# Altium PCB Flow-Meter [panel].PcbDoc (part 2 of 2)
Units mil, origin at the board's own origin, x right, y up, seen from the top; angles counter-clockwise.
Board outline 669.29 x 748.03 mil, 2 copper layers (Top Layer, Bottom Layer), stack 61.855 mil thick; 0 components, 7 nets, 832 pads, 0 vias.

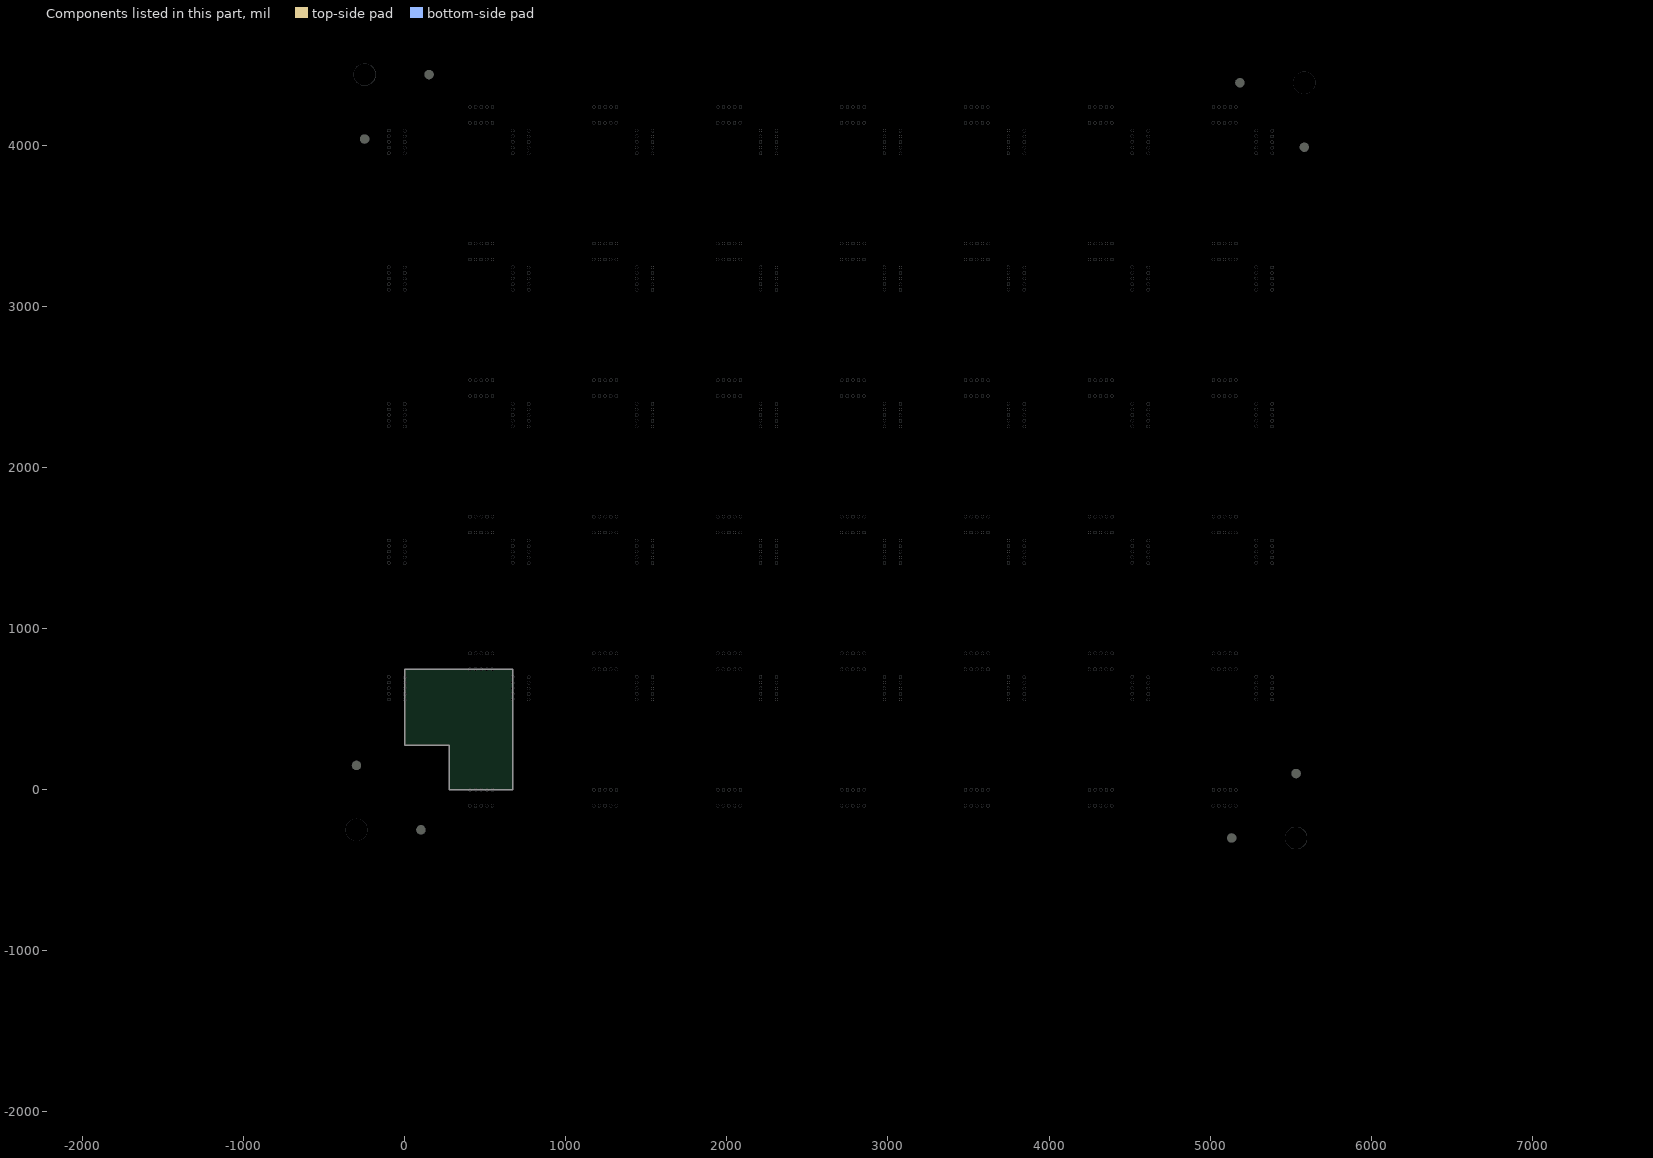
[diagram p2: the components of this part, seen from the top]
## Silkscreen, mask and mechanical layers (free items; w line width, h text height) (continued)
Bottom Paste:
  lines w7.87: -2070.08,-1784.25 1512.6,-1784.25 2142.52,-1784.25 2772.44,-1784.25 3402.36,-1784.25 4032.28,-1784.25 ; -2070.08,-1587.4 1512.6,-1587.4 5292.13,-1587.4 ; -1203.94,-1981.1 -1203.94,-1587.4 ; -692.13,-1981.1 -692.13,-1587.4 ; 803.94,-1981.1 803.94,-1587.4 ; 2142.52,-1981.1 2142.52,-1587.4 ; 2772.44,-1981.1 2772.44,-1587.4 ; 3402.36,-1981.1 3402.36,-1587.4 ; 4032.28,-1587.4 4032.28,-1981.1 4032.28,-1784.25 ; 4662.2,-1981.1 4662.2,-1587.4 ; 5626.77,-1981.1 5626.77,-1784.25 ; 7044.09,-1981.1 7044.09,-1784.25 ; 7536.22,-1784.25 5292.13,-1784.25 ; 1512.6,-1981.1 7536.22,-1981.1 7536.22,-800 5922.05,-800 5292.13,-800 ; 1512.6,-1981.1 1512.6,-800 ; 1512.6,-1981.1 -2070.08,-1981.1 -2070.08,-800 1512.6,-800 ; 1512.6,-800 5292.13,-800 ; 4032.28,-1784.25 4662.2,-1784.25 5292.13,-1784.25 ; 5292.13,-1784.25 5292.13,-1981.1 5292.13,-1784.25 ; 5292.13,-1784.25 5292.13,-800
  text "TITLE" at 1433.86,-918.11 h98.43
  text "NOTES:" at 5233.07,-918.11 h98.43
  text "1) PADS ARE 1:1 REDUCTION TO BE SPECIFIED BY THE ASSEMBLER" at 5233.07,-1036.22 h98.43
  text "2) VIEW ON SQUEEGEE SIDE DO NOT MIRROR" at 5233.07,-1154.33 h98.43
  text "AGRIGEL" at 7362.02,-1171.02 h393.7
  text ".PCB_TITLE" at 1315.75,-1233.07 h196.85
  text "3) STENCIL TYPE AND FRAMING TO BE SPECIFIED BY THE ASSEMBLER" at 5233.07,-1272.44 h98.43
  text "BOTTOM SIDE SOLDER STENCIL" at 1276.38,-1351.18 h98.43
  text "4) INDICATED FRAME REPRESENTS MAXIMIUM PANEL SIZE AND MUST" at 5233.07,-1390.55 h98.43
  text "BE CENTERED ON THE SOLDER STENCIL" at 5114.96,-1508.66 h98.43
  text "SHEET NO." at -1282.68,-1705.51 h98.43
  text "PCB VER" at -731.5,-1705.51 h98.43
  text ".PCB_Drawing Number" at 725.2,-1705.51 h98.43
  text "DWG NUMBER" at 1473.23,-1705.51 h98.43
  text ".PCB_ECRNo" at 1985.04,-1705.51 h98.43
  text ".PCB_DocRevision" at 2733.07,-1705.51 h98.43
  text ".PRINT_DATE" at 3284.25,-1705.51 h98.43
  text ".PCB_Approved" at 3914.17,-1705.51 h98.43
  text ".PCB_Checked" at 4544.09,-1705.51 h98.43
  text ".PCB_Drawn" at 5134.64,-1705.51 h98.43
  text "2" at -1951.97,-1902.36 h98.43
  text "OF" at -1755.12,-1902.36 h98.43
  text "2" at -1637.01,-1902.36 h98.43
  text "SHEET" at -1282.68,-1902.36 h98.43
  text ".Version" at -810.24,-1902.36 h98.43
  text ".Pcb_File_Name_No_Path" at 725.2,-1902.36 h98.43
  text "SOURCE" at 1473.23,-1902.36 h98.43
  text "ECR NO." at 1985.04,-1902.36 h98.43
  text "DOC REV." at 2654.33,-1902.36 h98.43
  text "DATE" at 3205.51,-1902.36 h98.43
  text "APPROVED" at 3953.54,-1902.36 h98.43
  text "CHECKED" at 4544.09,-1902.36 h98.43
  text "DRAWN" at 5134.64,-1902.36 h98.43
  text "GBP" at 5587.4,-1902.36 h98.43
  text ".PCB_Plot File" at 7004.72,-1902.36 h98.43
  text "PLOTFILE" at 7496.85,-1902.36 h98.43
Top Solder:
  circle w7.87: c-1000,-300 r98.43
  circle w7.87: c-1000,-300 r19.69
  circle w7.87: c-1000,-300 r59.06
  circle w7.87: c-1000,4440 r98.43
  circle w7.87: c-1000,4440 r19.69
  circle w7.87: c-1000,4440 r59.06
  circle w7.87: c6300,-300 r98.43
  circle w7.87: c6300,-300 r19.69
  circle w7.87: c6300,-300 r59.06
  rectangle: 1091.73,4336.02 1308.46,4463.98
  rectangle: 3891.73,-363.98 4108.46,-236.02
  lines w7.87: -2063.78,-1784.25 180.31,-1784.25 ; -1571.65,-1981.1 -1571.65,-1784.25 ; -1118.11,-300 -1000,-300 ; -1118.11,4440 -1000,4440 ; -1000,-418.11 -1000,-300 ; -1000,-181.89 -1000,-300 ; -1000,4321.89 -1000,4440 ; -1000,4558.11 -1000,4440 ; -881.89,-300 -1000,-300 ; -881.89,4440 -1000,4440 ; -154.33,-1981.1 -154.33,-1784.25 ; 180.31,-1981.1 180.31,-1784.25 ; 180.31,-1587.4 3959.84,-1587.4 7542.52,-1587.4 ; 180.31,-1390.55 3959.84,-1390.55 ; 180.31,-1193.7 3959.84,-1193.7 ; 180.31,-996.85 3959.84,-996.85 ; 810.24,-1981.1 810.24,-800 ; 1440.16,-800 1440.16,-1981.1 1440.16,-1784.25 ; 2070.08,-1981.1 2070.08,-800 ; 2700,-1981.1 2700,-800 ; 3329.92,-1981.1 3329.92,-800 ; 4668.5,-1981.1 4668.5,-1587.4 ; 6164.57,-1981.1 6164.57,-1587.4 ; 6181.89,-300 6300,-300 ; 6300,-418.11 6300,-300 ; 6300,-181.89 6300,-300 ; 6418.11,-300 6300,-300 ; 6676.38,-1981.1 6676.38,-1587.4 ; 7542.52,-1784.25 3959.84,-1784.25 3329.92,-1784.25 2700,-1784.25 2070.08,-1784.25 1440.16,-1784.25 ; 180.31,-1784.25 810.24,-1784.25 1440.16,-1784.25 ; 180.31,-1784.25 180.31,-800 ; 180.31,-800 3959.84,-800 ; 180.31,-800 -449.61,-800 -2063.78,-800 -2063.78,-1981.1 3959.84,-1981.1 ; 3959.84,-1981.1 7542.52,-1981.1 7542.52,-800 3959.84,-800 ; 3959.84,-1981.1 3959.84,-800
  text "TITLE" at 4038.58,-918.11 h98.43
  text "AGRIGEL" at -1896.32,-1171.02 h393.7
  text ".PCB_TITLE" at 4156.69,-1233.07 h196.85
  text "TOP SIDE SOLDER MASK" at 4156.69,-1390.55 h98.43
  text ".PCB_Drawn" at 337.8,-1705.51 h98.43
  text ".PCB_Checked" at 928.35,-1705.51 h98.43
  text ".PCB_Approved" at 1558.27,-1705.51 h98.43
  text ".PRINT_DATE" at 2188.19,-1705.51 h98.43
  text ".PCB_DocRevision" at 2739.37,-1705.51 h98.43
  text ".PCB_ECRNo" at 3487.4,-1705.51 h98.43
  text "DWG NUMBER" at 3999.21,-1705.51 h98.43
  text ".PCB_Drawing Number" at 4747.24,-1705.51 h98.43
  text "PCB VER" at 6203.94,-1705.51 h98.43
  text "SHEET NO." at 6755.12,-1705.51 h98.43
  text "PLOTFILE" at -2024.41,-1902.36 h98.43
  text ".PCB_Plot File" at -1532.28,-1902.36 h98.43
  text "GTS" at -114.96,-1902.36 h98.43
  text "DRAWN" at 337.8,-1902.36 h98.43
  text "CHECKED" at 928.35,-1902.36 h98.43
  text "APPROVED" at 1518.9,-1902.36 h98.43
  text "DATE" at 2266.93,-1902.36 h98.43
  text "DOC REV." at 2818.11,-1902.36 h98.43
  text "ECR NO." at 3487.4,-1902.36 h98.43
  text "SOURCE" at 3999.21,-1902.36 h98.43
  text ".Pcb_File_Name_No_Path" at 4747.24,-1902.36 h98.43
  text ".Version" at 6282.68,-1902.36 h98.43
  text "SHEET" at 6755.12,-1902.36 h98.43
  text "3" at 7109.45,-1902.36 h98.43
  text "OF" at 7227.56,-1902.36 h98.43
  text "7" at 7424.41,-1902.36 h98.43
Bottom Solder:
  circle w7.87: c-1000,-300 r98.43
  circle w7.87: c-1000,-300 r19.69
  circle w7.87: c-1000,-300 r59.06
  circle w7.87: c-1000,4440 r98.43
  circle w7.87: c-1000,4440 r19.69
  circle w7.87: c-1000,4440 r59.06
  circle w7.87: c6300,-300 r98.43
  circle w7.87: c6300,-300 r19.69
  circle w7.87: c6300,-300 r59.06
  rectangle: 1091.73,4336.02 1308.46,4463.98
  rectangle: 3891.73,-363.98 4108.46,-236.02
  lines w7.87: -2063.78,-1784.25 180.31,-1784.25 ; -1571.65,-1981.1 -1571.65,-1784.25 ; -1118.11,-300 -1000,-300 ; -1118.11,4440 -1000,4440 ; -1000,-418.11 -1000,-300 ; -1000,-181.89 -1000,-300 ; -1000,4321.89 -1000,4440 ; -1000,4558.11 -1000,4440 ; -881.89,-300 -1000,-300 ; -881.89,4440 -1000,4440 ; -154.33,-1981.1 -154.33,-1784.25 ; 180.31,-1981.1 180.31,-1784.25 ; 180.31,-1587.4 3959.84,-1587.4 7542.52,-1587.4 ; 180.31,-1390.55 3959.84,-1390.55 ; 180.31,-1193.7 3959.84,-1193.7 ; 180.31,-996.85 3959.84,-996.85 ; 810.24,-1981.1 810.24,-800 ; 1440.16,-800 1440.16,-1981.1 1440.16,-1784.25 ; 2070.08,-1981.1 2070.08,-800 ; 2700,-1981.1 2700,-800 ; 3329.92,-1981.1 3329.92,-800 ; 4668.5,-1981.1 4668.5,-1587.4 ; 6164.57,-1981.1 6164.57,-1587.4 ; 6181.89,-300 6300,-300 ; 6300,-418.11 6300,-300 ; 6300,-181.89 6300,-300 ; 6418.11,-300 6300,-300 ; 6676.38,-1981.1 6676.38,-1587.4 ; 7542.52,-1784.25 3959.84,-1784.25 3329.92,-1784.25 2700,-1784.25 2070.08,-1784.25 1440.16,-1784.25 ; 180.31,-1784.25 810.24,-1784.25 1440.16,-1784.25 ; 180.31,-1784.25 180.31,-800 ; 180.31,-800 3959.84,-800 ; 180.31,-800 -449.61,-800 -2063.78,-800 -2063.78,-1981.1 3959.84,-1981.1 ; 3959.84,-1981.1 7542.52,-1981.1 7542.52,-800 3959.84,-800 ; 3959.84,-1981.1 3959.84,-800
  text "TITLE" at 4038.58,-918.11 h98.43
  text "AGRIGEL" at -1896.32,-1171.02 h393.7
  text ".PCB_TITLE" at 4156.69,-1233.07 h196.85
  text "BOTTOM SIDE SOLDER MASK" at 4156.69,-1390.55 h98.43
  text ".PCB_Drawn" at 337.8,-1705.51 h98.43
  text ".PCB_Checked" at 928.35,-1705.51 h98.43
  text ".PCB_Approved" at 1558.27,-1705.51 h98.43
  text ".PRINT_DATE" at 2188.19,-1705.51 h98.43
  text ".PCB_DocRevision" at 2739.37,-1705.51 h98.43
  text ".PCB_ECRNo" at 3487.4,-1705.51 h98.43
  text "DWG NUMBER" at 3999.21,-1705.51 h98.43
  text ".PCB_Drawing Number" at 4747.24,-1705.51 h98.43
  text "PCB VER" at 6203.94,-1705.51 h98.43
  text "SHEET NO." at 6755.12,-1705.51 h98.43
  text "PLOTFILE" at -2024.41,-1902.36 h98.43
  text ".PCB_Plot File" at -1532.28,-1902.36 h98.43
  text "GBS" at -114.96,-1902.36 h98.43
  text "DRAWN" at 337.8,-1902.36 h98.43
  text "CHECKED" at 928.35,-1902.36 h98.43
  text "APPROVED" at 1518.9,-1902.36 h98.43
  text "DATE" at 2266.93,-1902.36 h98.43
  text "DOC REV." at 2818.11,-1902.36 h98.43
  text "ECR NO." at 3487.4,-1902.36 h98.43
  text "SOURCE" at 3999.21,-1902.36 h98.43
  text ".Pcb_File_Name_No_Path" at 4747.24,-1902.36 h98.43
  text ".Version" at 6282.68,-1902.36 h98.43
  text "SHEET" at 6755.12,-1902.36 h98.43
  text "6" at 7109.45,-1902.36 h98.43
  text "OF" at 7227.56,-1902.36 h98.43
  text "7" at 7424.41,-1902.36 h98.43
Board:
  drawing of 202 lines, arcs and shapes, not listed
Drill Drawing:
  circle w4.92: c4071.65,-4100 r118.11
  circle w4.92: c4071.65,-4100 r39.37
  region: -500,-500 -578.74,-539.37 -539.37,-578.74
  lines w7.87: -3511.02,-4281.1 -3511.02,7136.22 12630.71,7136.22 12630.71,-4281.1 ; -3510.51,-4280.28 -3510.51,-4297.01 -3487.87,-4297.01 ; -3487.4,-4296.85 12630.36,-4296.85 ; -1169.29,-775.59 -775.59,-775.59 -500,-500 ; 1488.6,-4100 3890.17,-4100 ; 1488.98,-4281.1 1488.98,-3100 3890.55,-3100 ; 1489.36,-3903.15 3914.17,-3903.15 4521.36,-3904.02 8323.62,-3903.15 ; 2236.63,-4296.85 2236.63,-4100 ; 3063.4,-4296.85 3063.4,-4100 ; 3890.55,-4102.02 3890.55,-3100 ; 3890.55,-3493.7 4520.47,-3493.7 8300,-3493.7 ; 3933.86,-4100 4485.04,-4100 ; 4071.65,-4237.79 4071.65,-3962.2 ; 4520.47,-4101.02 4520.47,-3100 ; 4520.47,-3690.55 8300,-3690.55 ; 4520.47,-3296.85 8300,-3296.85 ; 5150.39,-4281.1 5150.39,-3100 ; 5779.36,-4100 6433.86,-4100 7063.78,-4100 7693.7,-4100 8300.36,-4100 ; 5779.94,-4296.85 5779.94,-4100 5150.02,-4100 4520.09,-4100 ; 5780.31,-4281.1 5780.31,-3100 ; 6410.24,-4281.1 6410.24,-3100 ; 7040.16,-4281.1 7040.16,-3100 ; 7670.08,-4281.1 7670.08,-3100 ; 8299.62,-4296.85 12630.33,-4296.85 12630.33,-3903.15 8299.62,-3903.15 ; 8299.62,-4100 12630.33,-4100 ; 8300,-4296.02 8300,-3100 ; 8300,-1328.35 12630.71,-1328.35 ; 8300,-540.95 12630.71,-540.95 ; 8300,-344.1 12630.71,-344.1 ; 8300,247.4 12630.71,247.4 ; 8300,444.25 12630.71,444.25 ; 8300,636.38 8300.36,635.01 8300.36,52.75 ; 8300,831.65 12630.71,831.65 ; 8300,1028.5 12630.71,1028.5 12630.71,52.75 ; 8300,1225.35 12630.71,1225.35 ; 8300,1422.2 12630.71,1422.2 ; 8300,1619.05 12630.71,1619.05 ; 8300.36,50.77 12630.23,50.77 12630.23,247.64 ; 8300.36,51.62 8300.36,214.62 8300.36,215.62 ; 8300.36,627.56 8300.36,1422.41 8300,1423.78 8300,1815.9 12630.71,1815.9 12630.71,627.56 ; 8614.96,-737.8 8614.96,-344.1 ; 8614.96,52.75 8614.96,1621.65 ; 8654.33,-1722.05 8654.33,-1131.5 ; 9008.28,-4296.85 9008.28,-3903.15 ; 9244.88,-2903.15 9244.88,-2115.75 ; 10150.39,-737.8 10150.39,-344.1 ; 10150.39,52.75 10150.39,831.65 ; 10150.39,627.56 10150.39,1619.05 ; 10268.5,-1131.5 10347.24,-1131.5 10347.24,-1722.05 ; 11173.64,-4296.85 11173.64,-3903.15 ; 11685.45,-4296.85 11685.45,-3903.15 ; 11764.57,-737.8 11764.57,-344.1 ; 11764.57,52.75 11764.57,831.65 ; 11764.57,627.56 11764.57,1619.05 ; 12158.27,-737.8 12158.27,-344.1 ; 12158.27,52.75 12158.27,831.65 ; 12158.27,627.56 12158.27,1619.05 ; 12630.71,-3100 8300,-3100 ; 12630.71,-2312.6 8300,-2312.6 ; 12630.71,-1722.05 8300,-1722.05 8300,-1525.2 ; 12630.71,-1525.2 8300,-1525.2 ; 12630.71,-1131.5 8300,-1131.5 ; 12630.71,-934.65 8300,-934.65 8300,-1131.5 ; 3890.17,-4100 3890.17,-4296.85 3890.17,-4100 ; 3890.55,-3100 4520.47,-3100 ; 4520.09,-4296.85 4520.09,-4100 ; 4520.09,-4296.85 4520.09,-4100 ; 4520.09,-4296.85 4520.09,-4100 ; 4520.47,-3100 8300,-3100 ; 8300,-2903.15 12630.71,-2903.15 8300,-2903.15 ; 8300,-2903.15 8300,-1918.9 ; 8300,-2903.15 8300,-2706.3 ; 8300,-2706.3 8300,-2312.6 ; 8300,-2706.3 8300,-2509.45 12630.71,-2509.45 12630.71,-2706.3 8300,-2706.3 ; 8300,-2312.6 8300,-2115.75 ; 8300,-2115.75 12630.71,-2115.75 8300,-2115.75 ; 8300,-2115.75 8300,-1918.9 ; 8300,-1918.9 12630.71,-1918.9 8300,-1918.9 ; 8300,-1525.2 8300,-1131.5 ; 8300,634.8 12630.71,634.8 ; 8300,634.8 12630.71,634.8 ; 8300,634.8 12630.71,634.8 ; 8300,634.8 12630.71,634.8 ; 4229.13,-4139.37 4229.13,-4100 4229.13,-4060.63 4465.35,-3981.89 4465.35,-4218.11 4229.13,-4139.37 ; 8300,-737.8 8300,-147.25 12630.71,-147.25 12630.71,-737.8 8300,-737.8
  text ".Legend" at 8100,2000 h78.74
  text "LAYER BUILD DATA" at 9559.84,1697.79 h118.11
  text "SHT" at 8378.74,1500.94 h98.43
  text "DESCRIPTION" at 8693.7,1500.94 h98.43
  text "PLOTFILE" at 10229.13,1500.94 h98.43
  text "EXT" at 11882.68,1500.94 h98.43
  text "P/N" at 12315.75,1500.94 h98.43
  text "GD1" at 11848.31,1310.12 h98.43
  text "1" at 8457.48,1304.09 h98.43
  text "CUTTING & DRILLING DRAWING" at 8693.7,1304.09 h98.43
  text ".PCB_Plot File" at 10229.13,1304.09 h98.43
  text "-" at 12315.75,1304.09 h98.43
  text "GTO" at 11848.31,1113.27 h98.43
  text "2" at 8457.48,1107.24 h98.43
  text "TOP SIDE LEGEND" at 8693.7,1107.24 h98.43
  text ".PCB_Plot File" at 10229.13,1107.24 h98.43
  text "POS" at 12315.75,1107.24 h98.43
  text "GTS" at 11848.31,916.42 h98.43
  text "3" at 8457.48,910.39 h98.43
  text "TOP SIDE SOLDER MASK" at 8693.7,910.39 h98.43
  text ".PCB_Plot File" at 10229.13,910.39 h98.43
  text "NEG" at 12315.75,910.39 h98.43
  text "GTL" at 11848.31,719.57 h98.43
  text "4" at 8457.48,713.54 h98.43
  text "TOP SIDE" at 8693.7,713.54 h98.43
  text ".PCB_Plot File" at 10229.13,713.54 h98.43
  text "POS" at 12315.75,713.54 h98.43
  text "GBL" at 11848.31,529.02 h98.43
  text "BOTTOM SIDE" at 8693.7,522.99 h98.43
  text ".PCB_Plot File" at 10229.13,522.99 h98.43
  text "POS" at 12315.75,522.99 h98.43
  text "5" at 8457.48,516.69 h98.43
  text "GBS" at 11848.31,332.17 h98.43
  text "BOTTOM SIDE SOLDER MASK" at 8693.7,326.14 h98.43
  text ".PCB_Plot File" at 10229.13,326.14 h98.43
  text "NEG" at 12315.75,326.14 h98.43
  text "6" at 8457.48,319.84 h98.43
  text "GBO" at 11848.67,135.54 h98.43
  text "7" at 8457.84,129.51 h98.43
  text "BOTTOM SIDE LEGEND" at 8694.06,129.51 h98.43
  text ".PCB_Plot File" at 10229.5,129.51 h98.43
  text "POS" at 12316.11,129.51 h98.43
  text "SOLDER STENCIL DATA" at 9559.84,-265.35 h118.11
  text "SHT" at 8378.74,-462.2 h98.43
  text "DESCRIPTION" at 8693.7,-462.2 h98.43
  text "PLOTFILE" at 10229.13,-462.2 h98.43
  text "EXT" at 11882.68,-462.2 h98.43
  text "P/N" at 12315.75,-462.2 h98.43
  text "GTP" at 11848.31,-653.02 h98.43
  text "1" at 8457.48,-659.06 h98.43
  text "TOP SIDE SOLDER STENCIL" at 8693.7,-659.06 h98.43
  text ".PCB_Plot File" at 10229.13,-659.06 h98.43
  text "POS" at 12315.75,-659.06 h98.43
  text "NC DRILL" at -1169.29,-854.33 h78.74
  text "ORIGIN" at -1169.29,-933.07 h78.74
  text "X = 0 ; Y = 0" at -1169.29,-1011.81 h78.74
  text "MATERIAL" at 9992.91,-1052.76 h118.11
  text "ITEM" at 8378.74,-1249.61 h98.43
  text "FINAL THICKNESS" at 9008.66,-1249.61 h98.43
  text "MATERIAL" at 10898.42,-1249.61 h98.43
  text "Cu" at 8378.74,-1446.46 h98.43
  text "35um (ON ALL LAYERS)" at 9008.66,-1446.46 h98.43
  text "COPPER CLAD" at 10898.42,-1446.46 h98.43
  text "PCB" at 8378.74,-1643.31 h98.43
  text "1.60mm" at 9008.66,-1643.31 h98.43
  text "NEMA FR4" at 10898.42,-1643.31 h98.43
  text "FINISH" at 9953.54,-2037.01 h118.11
  text "ITEM" at 8418.11,-2233.86 h98.43
  text "DESCRIPTION" at 9362.99,-2233.86 h98.43
  text "PCB" at 8418.11,-2430.71 h98.43
  text "IMMERSION GOLD" at 9362.99,-2430.71 h98.43
  text "SOLDER MASK" at 8418.11,-2627.56 h98.43
  text "GREEN PHOTO-IMAGEABLE" at 9362.99,-2627.56 h98.43
  text "LEGEND" at 8418.11,-2824.41 h98.43
  text "WHITE EPOXY" at 9362.99,-2824.41 h98.43
  text "TITLE" at 8378.74,-3218.11 h98.43
  text "UNITS" at 4087.4,-3257.48 h98.43
  text "METRIC" at 4048.03,-3375.59 h98.43
  text "AGRIGEL" at 1656.44,-3471.02 h393.7
  text ".PCB_TITLE" at 8614.96,-3493.7 h196.85
  text "(CUTTING & DRILLING DRAWING)" at 8654.33,-3611.81 h98.43
  text "SCALE" at 4048.03,-3651.18 h98.43
  text "N/A" at 4126.77,-3769.29 h98.43
  text "TOLERANCES UNLESS OTHERWISE STATED" at 1764.57,-4005.51 h98.43
  text ".PCB_Drawn" at 4677.95,-4005.51 h98.43
  text ".PCB_Checked" at 5268.5,-4005.51 h98.43
  text ".PCB_Approved" at 5898.42,-4005.51 h98.43
  text ".PRINT_DATE" at 6528.35,-4005.51 h98.43
  text ".PCB_DocRevision" at 7079.53,-4005.51 h98.43
  text ".PCB_ECRNo" at 7827.56,-4005.51 h98.43
  text "DWG NUMBER" at 8315.37,-4005.51 h98.43
  text ".PCB_Drawing Number" at 9063.4,-4005.51 h98.43
  text "PCB VER" at 11189.39,-4005.51 h98.43
  text "SHEET NO." at 11976.79,-4005.51 h98.43
  text "1 = +/-0.2" at 1661.83,-4202.36 h98.43
  text "1.0 = +/-0.1" at 2409.86,-4202.36 h98.43
  text "1.00 = +/-0.5" at 3197.26,-4202.36 h98.43
  text "DRAWN" at 4653.95,-4202.36 h98.43
  text "CHECKED" at 5244.5,-4202.36 h98.43
  text "APPROVED" at 5859.05,-4202.36 h98.43
  text "DATE" at 6607.09,-4202.36 h98.43
  text "DOC REV." at 7158.27,-4202.36 h98.43
  text "ECR NO." at 7827.56,-4202.36 h98.43
  text "SOURCE" at 8315.37,-4202.36 h98.43
  text ".Pcb_File_Name_No_Path" at 9063.4,-4202.36 h98.43
  text ".Version" at 11268.13,-4202.36 h98.43
  text "SHEET" at 11740.57,-4202.36 h98.43
  text "1" at 12094.9,-4202.36 h98.43
  text "OF" at 12213.01,-4202.36 h98.43
  text "7" at 12409.86,-4202.36 h98.43

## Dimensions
-500,-500 to 5785,-500 on Drill Drawing
-500,-500 to -500,4640 on Drill Drawing

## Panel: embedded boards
"Flow-Meter.PcbDoc" at 0,0, 5 rows x 7 columns, spacing 848.03 x 769.29, rotation 0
